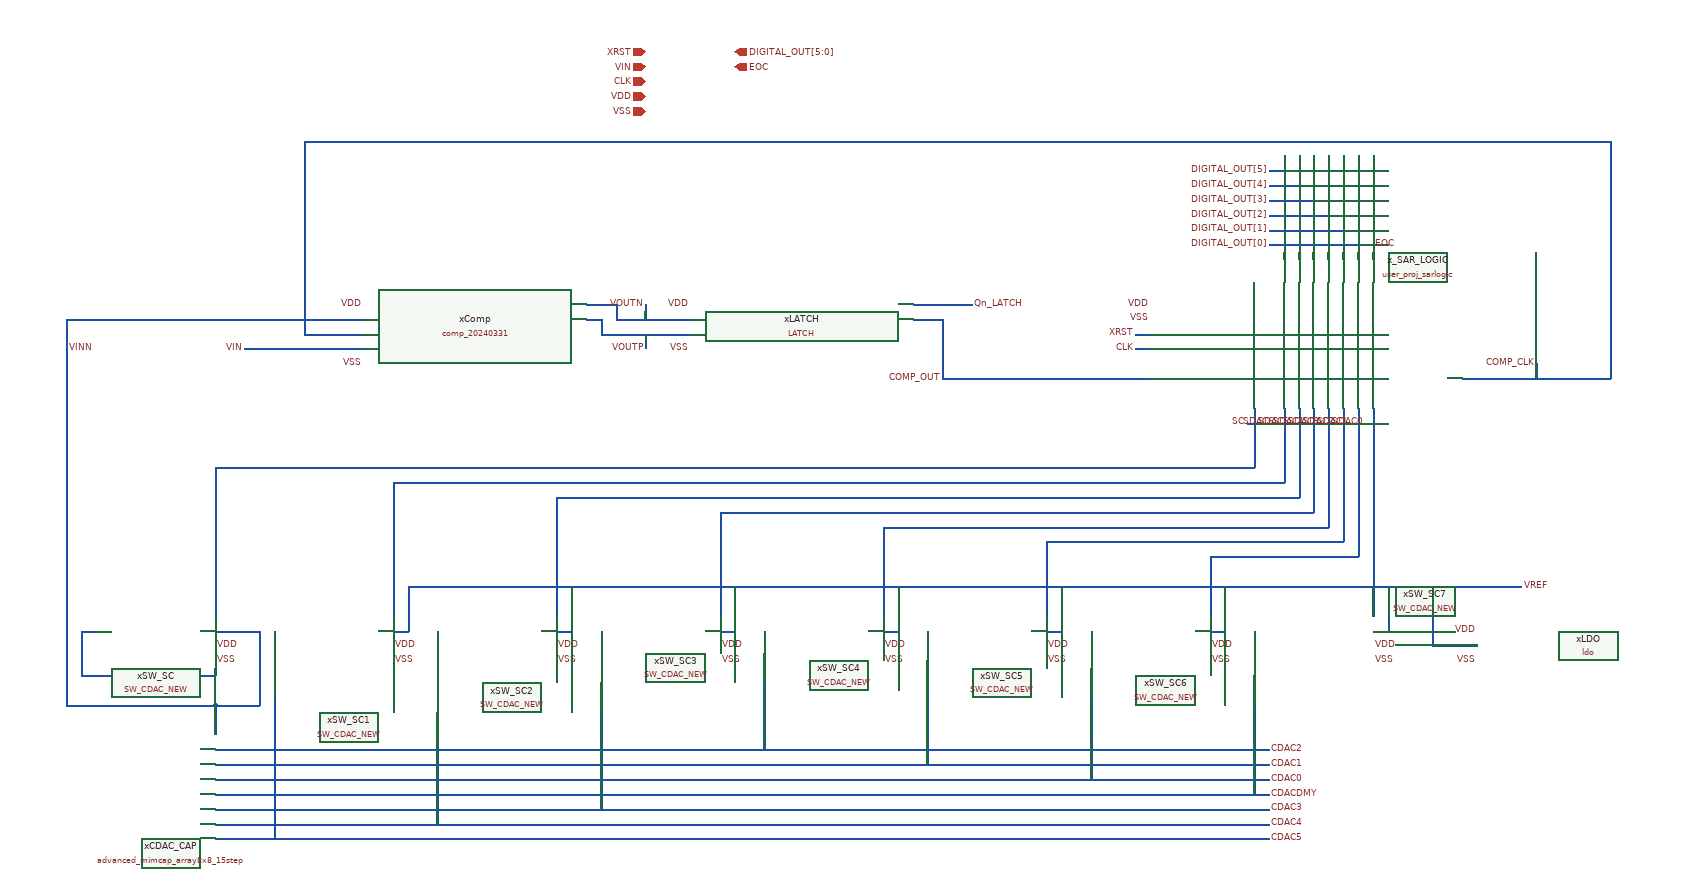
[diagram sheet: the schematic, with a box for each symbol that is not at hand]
v {xschem version=3.4.5 file_version=1.2
}
G {}
K {}
V {}
S {}
E {}
N 2480 -820 2760 -820 {
lab=COMP_OUT}
N 2740 -860 2760 -860 {
lab=CLK}
N 2740 -880 2760 -880 {
lab=XRST}
N 3060 -780 3060 -690 {
lab=SDAC0}
N 3050 -760 3060 -760 {
lab=SDAC0}
N 3040 -780 3040 -690 {
lab=SDAC1}
N 3030 -760 3040 -760 {
lab=SDAC1}
N 3020 -780 3020 -690 {
lab=SDAC2}
N 3010 -760 3020 -760 {
lab=SDAC2}
N 3000 -780 3000 -690 {
lab=SDAC3}
N 2990 -760 3000 -760 {
lab=SDAC3}
N 2980 -780 2980 -690 {
lab=SDAC4}
N 2970 -760 2980 -760 {
lab=SDAC4}
N 2960 -780 2960 -690 {
lab=SDAC5}
N 2950 -760 2960 -760 {
lab=SDAC5}
N 2940 -780 2940 -690 {
lab=SDAC6}
N 2930 -760 2940 -760 {
lab=SDAC6}
N 2900 -780 2900 -700 {
lab=SC}
N 2890 -760 2900 -760 {
lab=SC}
N 3180 -820 3380 -820 {
lab=COMP_CLK}
N 3280 -840 3280 -820 {
lab=COMP_CLK}
N 2000 -920 2040 -920 {
lab=VOUTN}
N 2000 -900 2020 -900 {
lab=VOUTP}
N 1500 -320 2920 -320 {
lab=CDAC2}
N 1500 -300 2920 -300 {
lab=CDAC1}
N 1500 -280 2920 -280 {
lab=CDAC0}
N 1500 -260 2920 -260 {
lab=CDACDMY}
N 1500 -240 2920 -240 {
lab=CDAC3}
N 1500 -220 2920 -220 {
lab=CDAC4}
N 1500 -200 2920 -200 {
lab=CDAC5}
N 1740 -680 2940 -680 {
lab=SDAC6}
N 1740 -680 1740 -500 {
lab=SDAC6}
N 1960 -660 1960 -500 {
lab=SDAC5}
N 1960 -660 2960 -660 {
lab=SDAC5}
N 2180 -640 2980 -640 {
lab=SDAC4}
N 2180 -640 2180 -500 {
lab=SDAC4}
N 2400 -620 2400 -500 {
lab=SDAC3}
N 2400 -620 3000 -620 {
lab=SDAC3}
N 2620 -600 3020 -600 {
lab=SDAC2}
N 2620 -600 2620 -500 {
lab=SDAC2}
N 2840 -580 2840 -500 {
lab=SDAC1}
N 3060 -690 3060 -500 {
lab=SDAC0}
N 1500 -700 2900 -700 {
lab=SC}
N 1500 -700 1500 -500 {
lab=SC}
N 1320 -480 1340 -480 {
lab=VSS}
N 1320 -480 1320 -420 {
lab=VSS}
N 1320 -420 1500 -420 {
lab=VSS}
N 1500 -440 1500 -420 {
lab=VSS}
N 1500 -380 1500 -340 {
lab=VINN}
N 1300 -380 1500 -380 {
lab=VINN}
N 1300 -900 1300 -380 {
lab=VINN}
N 1300 -900 1700 -900 {
lab=VINN}
N 1500 -480 1560 -480 {
lab=VINN}
N 1560 -480 1560 -380 {
lab=VINN}
N 1500 -380 1560 -380 {
lab=VINN}
N 2840 -580 3040 -580 {
lab=SDAC1}
N 1620 -880 1700 -880 {
lab=COMP_CLK}
N 1620 -1140 1620 -880 {
lab=COMP_CLK}
N 1620 -1140 3380 -1140 {
lab=COMP_CLK}
N 3380 -1140 3380 -820 {
lab=COMP_CLK}
N 2440 -900 2480 -900 {
lab=COMP_OUT}
N 2480 -900 2480 -820 {
lab=COMP_OUT}
N 2440 -920 2520 -920 {
lab=Qn_LATCH}
N 1760 -540 3260 -540 {
lab=VREF}
N 1740 -480 1760 -480 {
lab=VREF}
N 1760 -540 1760 -480 {
lab=VREF}
N 1960 -480 1980 -480 {
lab=VREF}
N 1980 -540 1980 -480 {
lab=VREF}
N 2180 -480 2200 -480 {
lab=VREF}
N 2200 -540 2200 -480 {
lab=VREF}
N 2400 -480 2420 -480 {
lab=VREF}
N 2420 -540 2420 -480 {
lab=VREF}
N 2620 -480 2640 -480 {
lab=VREF}
N 2640 -540 2640 -480 {
lab=VREF}
N 2840 -480 2860 -480 {
lab=VREF}
N 2860 -540 2860 -480 {
lab=VREF}
N 3060 -480 3080 -480 {
lab=VREF}
N 3080 -540 3080 -480 {
lab=VREF}
N 1540 -860 1700 -860 {
lab=VIN}
N 2080 -880 2080 -860 {
lab=VOUTP}
N 2080 -920 2080 -900 {
lab=VOUTN}
N 2040 -920 2040 -900 {
lab=VOUTN}
N 2940 -690 2940 -680 {
lab=SDAC6}
N 2960 -690 2960 -660 {
lab=SDAC5}
N 2980 -690 2980 -640 {
lab=SDAC4}
N 3000 -690 3000 -620 {
lab=SDAC3}
N 3020 -690 3020 -600 {
lab=SDAC2}
N 3040 -690 3040 -580 {
lab=SDAC1}
N 2900 -480 2900 -260 {
lab=CDACDMY}
N 2680 -480 2680 -280 {
lab=CDAC0}
N 2460 -480 2460 -300 {
lab=CDAC1}
N 2240 -480 2240 -320 {
lab=CDAC2}
N 2020 -480 2020 -240 {
lab=CDAC3}
N 1800 -480 1800 -220 {
lab=CDAC4}
N 1580 -480 1580 -200 {
lab=CDAC5}
N 2940 -1120 2940 -980 {
lab=DIGITAL_OUT[5]}
N 2920 -1100 2940 -1100 {
lab=DIGITAL_OUT[5]}
N 2920 -1080 2960 -1080 {
lab=DIGITAL_OUT[4]}
N 2920 -1060 2980 -1060 {
lab=DIGITAL_OUT[3]}
N 2920 -1040 3000 -1040 {
lab=DIGITAL_OUT[2]}
N 2920 -1020 3020 -1020 {
lab=DIGITAL_OUT[1]}
N 2920 -1000 3040 -1000 {
lab=DIGITAL_OUT[0]}
N 2960 -1120 2960 -980 {
lab=DIGITAL_OUT[4]}
N 2980 -1120 2980 -980 {
lab=DIGITAL_OUT[3]}
N 3000 -1120 3000 -980 {
lab=DIGITAL_OUT[2]}
N 3020 -1120 3020 -980 {
lab=DIGITAL_OUT[1]}
N 3040 -1120 3040 -980 {
lab=DIGITAL_OUT[0]}
N 3060 -1120 3060 -980 {
lab=EOC}
N 2020 -900 2020 -880 {
lab=VOUTP}
N 2020 -880 2140 -880 {
lab=VOUTP}
N 2040 -900 2140 -900 {
lab=VOUTN}
N 3140 -460 3200 -460 {
lab=VREF}
N 3140 -540 3140 -460 {
lab=VREF}
C {user_proj_sarlogic.sym} 2970 -870 0 0 {name=x_SAR_LOGIC}
C {devices/lab_pin.sym} 2740 -860 0 0 {name=p5 sig_type=std_logic lab=CLK}
C {devices/lab_pin.sym} 2740 -880 0 0 {name=p7 sig_type=std_logic lab=XRST}
C {devices/lab_pin.sym} 3050 -760 3 0 {name=p10 sig_type=std_logic lab=SDAC0}
C {devices/lab_pin.sym} 3030 -760 3 0 {name=p11 sig_type=std_logic lab=SDAC1}
C {devices/lab_pin.sym} 3010 -760 3 0 {name=p12 sig_type=std_logic lab=SDAC2}
C {devices/lab_pin.sym} 2990 -760 3 0 {name=p13 sig_type=std_logic lab=SDAC3}
C {devices/lab_pin.sym} 2970 -760 3 0 {name=p14 sig_type=std_logic lab=SDAC4}
C {devices/lab_pin.sym} 2950 -760 3 0 {name=p15 sig_type=std_logic lab=SDAC5}
C {devices/lab_pin.sym} 2930 -760 3 0 {name=p16 sig_type=std_logic lab=SDAC6}
C {devices/lab_pin.sym} 2890 -760 3 0 {name=p19 sig_type=std_logic lab=SC}
C {devices/lab_pin.sym} 3280 -840 0 0 {name=p20 sig_type=std_logic lab=COMP_CLK}
C {advanced_mimcap_array8x8_15step.sym} 1350 -270 0 0 {name=xCDAC_CAP}
C {comp_20240331.sym} 1850 -880 0 0 {name=xComp}
C {SW_CDAC_NEW.sym} 1500 -500 0 1 {name=xSW_SC}
C {devices/lab_pin.sym} 1500 -460 2 0 {name=p1 sig_type=std_logic lab=VDD}
C {devices/lab_pin.sym} 1740 -460 2 0 {name=p3 sig_type=std_logic lab=VDD}
C {devices/lab_pin.sym} 1960 -460 2 0 {name=p4 sig_type=std_logic lab=VDD}
C {devices/lab_pin.sym} 2180 -460 2 0 {name=p6 sig_type=std_logic lab=VDD}
C {devices/lab_pin.sym} 2400 -460 2 0 {name=p8 sig_type=std_logic lab=VDD}
C {devices/lab_pin.sym} 2620 -460 2 0 {name=p22 sig_type=std_logic lab=VDD}
C {devices/lab_pin.sym} 2840 -460 2 0 {name=p23 sig_type=std_logic lab=VDD}
C {devices/lab_pin.sym} 3060 -460 2 0 {name=p24 sig_type=std_logic lab=VDD}
C {devices/lab_pin.sym} 1540 -860 0 0 {name=p26 sig_type=std_logic lab=VIN}
C {devices/lab_pin.sym} 2080 -920 0 0 {name=p27 sig_type=std_logic lab=VOUTN}
C {devices/lab_pin.sym} 2080 -860 2 1 {name=p28 sig_type=std_logic lab=VOUTP}
C {devices/lab_pin.sym} 2920 -320 0 1 {name=p29 sig_type=std_logic lab=CDAC2}
C {devices/lab_pin.sym} 2920 -300 0 1 {name=p30 sig_type=std_logic lab=CDAC1}
C {devices/lab_pin.sym} 2920 -280 0 1 {name=p31 sig_type=std_logic lab=CDAC0}
C {devices/lab_pin.sym} 2920 -260 0 1 {name=p32 sig_type=std_logic lab=CDACDMY}
C {devices/lab_pin.sym} 2920 -240 0 1 {name=p33 sig_type=std_logic lab=CDAC3}
C {devices/lab_pin.sym} 2920 -220 0 1 {name=p34 sig_type=std_logic lab=CDAC4}
C {devices/lab_pin.sym} 2920 -200 0 1 {name=p35 sig_type=std_logic lab=CDAC5}
C {devices/lab_pin.sym} 1300 -860 0 1 {name=p36 sig_type=std_logic lab=VINN}
C {devices/lab_pin.sym} 3260 -540 2 0 {name=p37 sig_type=std_logic lab=VREF}
C {devices/lab_pin.sym} 2520 -920 2 0 {name=p38 sig_type=std_logic lab=Qn_LATCH}
C {devices/lab_pin.sym} 2480 -820 0 0 {name=p39 sig_type=std_logic lab=COMP_OUT}
C {devices/lab_pin.sym} 2920 -1100 0 0 {name=p18 sig_type=std_logic lab=DIGITAL_OUT[5]}
C {devices/lab_pin.sym} 2920 -1080 0 0 {name=p21 sig_type=std_logic lab=DIGITAL_OUT[4]}
C {devices/lab_pin.sym} 2920 -1060 0 0 {name=p40 sig_type=std_logic lab=DIGITAL_OUT[3]}
C {devices/lab_pin.sym} 2920 -1040 0 0 {name=p41 sig_type=std_logic lab=DIGITAL_OUT[2]}
C {devices/lab_pin.sym} 2920 -1020 0 0 {name=p42 sig_type=std_logic lab=DIGITAL_OUT[1]}
C {devices/lab_pin.sym} 2920 -1000 0 0 {name=p43 sig_type=std_logic lab=DIGITAL_OUT[0]}
C {devices/lab_pin.sym} 3060 -1000 2 0 {name=p17 sig_type=std_logic lab=EOC}
C {ldo.sym} 3350 -460 0 1 {name=xLDO}
C {devices/ipin.sym} 2080 -1240 0 0 {name=p44 lab=VIN}
C {devices/ipin.sym} 2080 -1260 0 0 {name=p45 lab=XRST}
C {devices/ipin.sym} 2080 -1220 0 0 {name=p46 lab=CLK}
C {devices/opin.sym} 2200 -1260 0 0 {name=p47 lab=DIGITAL_OUT[5:0]}
C {devices/opin.sym} 2200 -1240 0 0 {name=p48 lab=EOC}
C {devices/iopin.sym} 2080 -1200 0 0 {name=p49 lab=VDD}
C {devices/iopin.sym} 2080 -1180 0 0 {name=p50 lab=VSS}
C {devices/lab_pin.sym} 1700 -920 0 0 {name=p51 sig_type=std_logic lab=VDD}
C {devices/lab_pin.sym} 2140 -920 0 0 {name=p52 sig_type=std_logic lab=VDD}
C {devices/lab_pin.sym} 2760 -920 0 0 {name=p53 sig_type=std_logic lab=VDD}
C {devices/lab_pin.sym} 3200 -480 0 0 {name=p54 sig_type=std_logic lab=VDD}
C {devices/lab_pin.sym} 1700 -840 0 0 {name=p2 sig_type=std_logic lab=VSS}
C {devices/lab_pin.sym} 2140 -860 0 0 {name=p9 sig_type=std_logic lab=VSS}
C {devices/lab_pin.sym} 2760 -900 0 0 {name=p25 sig_type=std_logic lab=VSS}
C {devices/lab_pin.sym} 3200 -440 0 0 {name=p55 sig_type=std_logic lab=VSS}
C {devices/lab_pin.sym} 1500 -440 2 0 {name=p56 sig_type=std_logic lab=VSS}
C {devices/lab_pin.sym} 1740 -440 2 0 {name=p57 sig_type=std_logic lab=VSS}
C {devices/lab_pin.sym} 1960 -440 2 0 {name=p58 sig_type=std_logic lab=VSS}
C {devices/lab_pin.sym} 2180 -440 2 0 {name=p59 sig_type=std_logic lab=VSS}
C {devices/lab_pin.sym} 2400 -440 2 0 {name=p60 sig_type=std_logic lab=VSS}
C {devices/lab_pin.sym} 2620 -440 2 0 {name=p61 sig_type=std_logic lab=VSS}
C {devices/lab_pin.sym} 2840 -440 2 0 {name=p62 sig_type=std_logic lab=VSS}
C {devices/lab_pin.sym} 3060 -440 2 0 {name=p63 sig_type=std_logic lab=VSS}
C {LATCH.sym} 2290 -890 0 0 {name=xLATCH}
C {SW_CDAC_NEW.sym} 1740 -500 0 1 {name=xSW_SC1}
C {SW_CDAC_NEW.sym} 1960 -500 0 1 {name=xSW_SC2}
C {SW_CDAC_NEW.sym} 2180 -500 0 1 {name=xSW_SC3}
C {SW_CDAC_NEW.sym} 2400 -500 0 1 {name=xSW_SC4}
C {SW_CDAC_NEW.sym} 2620 -500 0 1 {name=xSW_SC5}
C {SW_CDAC_NEW.sym} 2840 -500 0 1 {name=xSW_SC6}
C {SW_CDAC_NEW.sym} 3060 -500 0 1 {name=xSW_SC7}
